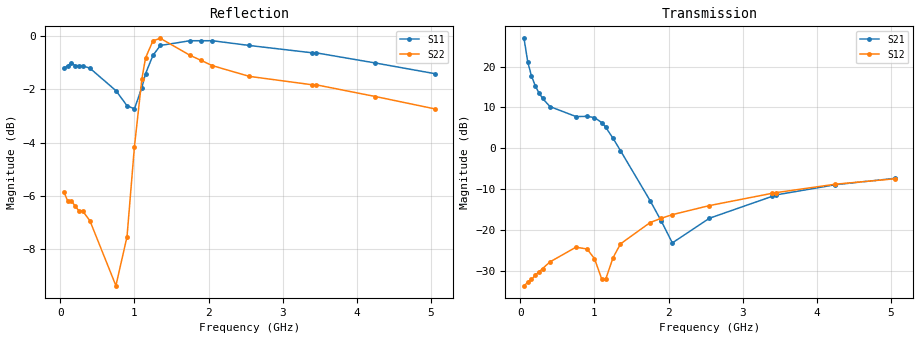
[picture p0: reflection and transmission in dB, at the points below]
!AT-33225
!S-PARAMETERS at Vce=4.8V  Ic=100mA.  LAST UPDATED 08-05-96
# ghz s ma r 50
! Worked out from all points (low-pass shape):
!   101 points, 50 MHz to 5.05 GHz, reference 50 ohm
!   highest |S21| = 26.88 dB at 50 MHz (marker M1); lowest = -23.1 dB at 2.05 GHz (marker M2)
!   |S21| within 3 dB of the highest: start of sweep to 76.04 MHz
!   lowest |S11| = -2.7 dB at 1 GHz (marker M3), VSWR 6.41, Z = 7.81 + j1.7 ohm
!   |S11| at or under -10 dB: nowhere
!   |S22| runs from -9.4 to -0.1 dB; largest |S21 - S12| = 22
!   S11 on the Smith chart (normalised r, x): 50 MHz: 0.07, -0.18; 400 MHz: 0.07, +0.04; 1.9 GHz: 0.01, +0.18; 3.45 GHz: 0.04, +0.37; 5.05 GHz: 0.11, +0.60
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0.05  0.87 -160.0  22.09 101.0  0.021 24.0  0.51 -144.0
0.1  0.88 -171.0  11.38 91.0  0.023 27.0  0.49 -162.0
0.15  0.89 -176.0  7.7 86.0  0.025 32.0  0.49 -169.0
0.2  0.88 -179.0  5.86 82.0  0.028 37.0  0.48 -173.0
0.25  0.88 179.0  4.79 78.0  0.031 40.0  0.47 -175.0
0.3  0.88 178.0  4.08 75.0  0.034 43.0  0.47 -176.0
0.4  0.87 175.0  3.24 68.0  0.041 46.0  0.45 -178.0
0.75  0.79 169.0  2.45 36.0  0.062 38.0  0.34 -162.0
0.9  0.74 172.0  2.46 13.0  0.059 27.0  0.42 -137.0
1  0.73 176.0  2.38 -9.0  0.045 20.0  0.62 -133.0
1.1  0.8 180.0  2.06 -33.0  0.025 39.0  0.83 -142.0
1.15  0.85 180.0  1.82 -45.0  0.025 70.0  0.91 -148.0
1.25  0.92 177.0  1.33 -65.0  0.046 94.0  0.98 -160.0
1.35  0.96 174.0  0.94 -81.0  0.068 93.0  0.99 -169.0
1.75  0.98 163.0  0.23 -123.0  0.124 79.0  0.92 172.0
1.9  0.98 160.0  0.13 -144.0  0.14 75.0  0.9 167.0
2.05  0.98 158.0  0.07 175.0  0.155 72.0  0.88 164.0
2.55  0.96 151.0  0.14 82.0  0.2 63.0  0.84 154.0
3.4  0.93 140.0  0.26 53.0  0.283 50.0  0.81 138.0
3.45  0.93 139.0  0.27 52.0  0.288 49.0  0.81 137.0
4.25  0.89 129.0  0.36 35.0  0.365 33.0  0.77 118.0
5.05  0.85 118.0  0.43 18.0  0.425 18.0  0.73 96.0
